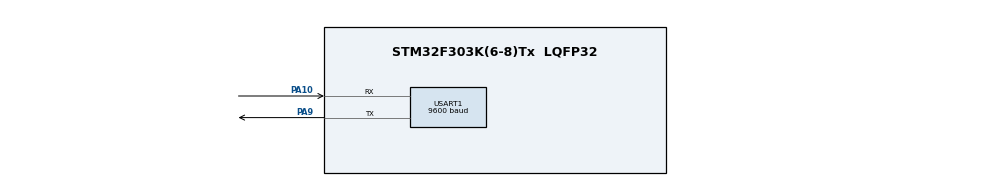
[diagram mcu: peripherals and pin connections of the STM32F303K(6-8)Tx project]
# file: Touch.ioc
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Mcu.Family=STM32F3
Mcu.Name=STM32F303K(6-8)Tx
Mcu.Package=LQFP32
NVIC.PriorityGroup=NVIC_PRIORITYGROUP_4
PA10.Mode=Asynchronous
PA10.Signal=USART1_RX
PA13.GPIO_Label=SWDIO
PA13.Mode=Serial_Wire
PA13.Signal=SYS_JTMS-SWDIO
PA14.GPIO_Label=SWCLK
PA14.Mode=Serial_Wire
PA14.Signal=SYS_JTCK-SWCLK
PA15.GPIO_Label=VCP_RX
PA15.Signal=USART2_RX
PA2.GPIO_Label=VCP_TX
PA2.Signal=USART2_TX
PA9.Mode=Asynchronous
PA9.Signal=USART1_TX
PF0\ /\ OSC_IN.GPIO_Label=MCO
PF0\ /\ OSC_IN.Signal=RCC_OSC_IN
ProjectManager.HeapSize=0x200
ProjectManager.StackSize=0x400
ProjectManager.TargetToolchain=SW4STM32
RCC.AHBFreq_Value=8000000
RCC.APB1Freq_Value=8000000
RCC.APB2Freq_Value=8000000
RCC.CortexFreq_Value=8000000
RCC.HSE_VALUE=8000000
RCC.HSI_VALUE=8000000
RCC.SYSCLKFreq_VALUE=8000000
USART1.BaudRate=9600
USART1.VirtualMode-Asynchronous=VM_ASYNC
USART1.WordLength=WORDLENGTH_8B
board=NUCLEO-F303K8

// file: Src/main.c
/**
  ******************************************************************************
  * @file           : main.c
  * @brief          : Main program body
  ******************************************************************************
  ** This notice applies to any and all portions of this file
  * that are not between comment pairs USER CODE BEGIN and
  * USER CODE END. Other portions of this file, whether
  * inserted by the user or by software development tools
  * are owned by their respective copyright owners.
  *
  * COPYRIGHT(c) 2018 STMicroelectronics
  *
  * Redistribution and use in source and binary forms, with or without modification,
  * are permitted provided that the following conditions are met:
  *   1. Redistributions of source code must retain the above copyright notice,
  *      this list of conditions and the following disclaimer.
  *   2. Redistributions in binary form must reproduce the above copyright notice,
  *      this list of conditions and the following disclaimer in the documentation
  *      and/or other materials provided with the distribution.
  *   3. Neither the name of STMicroelectronics nor the names of its contributors
  *      may be used to endorse or promote products derived from this software
  *      without specific prior written permission.
  *
  * THIS SOFTWARE IS PROVIDED BY THE COPYRIGHT HOLDERS AND CONTRIBUTORS "AS IS"
  * AND ANY EXPRESS OR IMPLIED WARRANTIES, INCLUDING, BUT NOT LIMITED TO, THE
  * IMPLIED WARRANTIES OF MERCHANTABILITY AND FITNESS FOR A PARTICULAR PURPOSE ARE
  * DISCLAIMED. IN NO EVENT SHALL THE COPYRIGHT HOLDER OR CONTRIBUTORS BE LIABLE
  * FOR ANY DIRECT, INDIRECT, INCIDENTAL, SPECIAL, EXEMPLARY, OR CONSEQUENTIAL
  * DAMAGES (INCLUDING, BUT NOT LIMITED TO, PROCUREMENT OF SUBSTITUTE GOODS OR
  * SERVICES; LOSS OF USE, DATA, OR PROFITS; OR BUSINESS INTERRUPTION) HOWEVER
  * CAUSED AND ON ANY THEORY OF LIABILITY, WHETHER IN CONTRACT, STRICT LIABILITY,
  * OR TORT (INCLUDING NEGLIGENCE OR OTHERWISE) ARISING IN ANY WAY OUT OF THE USE
  * OF THIS SOFTWARE, EVEN IF ADVISED OF THE POSSIBILITY OF SUCH DAMAGE.
  *
  ******************************************************************************
  */
#include "main.h"
#include "stm32f0xx_hal.h"

/* USER CODE BEGIN Includes */
#include "touch.h"
#include "identification.h"
/* USER CODE END Includes */

UART_HandleTypeDef huart1;

/* USER CODE BEGIN PV */
/* Private variables ---------------------------------------------------------*/

/* USER CODE END PV */

void SystemClock_Config(void);
static void MX_GPIO_Init(void);
static void MX_USART1_UART_Init(void);

/* USER CODE BEGIN PFP */
/* Private function prototypes -----------------------------------------------*/

/* USER CODE END PFP */

int main(void)
{
  /* USER CODE BEGIN 1 */
	//int light = 0;
  /* USER CODE END 1 */

  /* MCU Configuration----------------------------------------------------------*/

  /* Reset of all peripherals, Initializes the Flash interface and the Systick. */
  HAL_Init();

  /* Configure the system clock */
  SystemClock_Config();

  /* Initialize all configured peripherals */
  MX_GPIO_Init();
  MX_USART1_UART_Init();
  /* USER CODE BEGIN 2 */
  touch_open(0);
  touch_bakcklight(1);
  printf("Touch Connected");
  /* USER CODE END 2 */

  /* Infinite loop */
  while (1)
  {

  /* USER CODE BEGIN 3 */
//	  touch_bakcklight(0);
//	  HAL_Delay(1000);
//

//	  HAL_Delay(1000);
//	  touch_enroll_start(10);
//	  while(!touch_is_press_finger()){
//		  HAL_Delay(100);
//	  }
//		touch_capture_finger();
//		touch_enroll_1();
//		  while(touch_is_press_finger()){
//			  HAL_Delay(100);
//		  }
//		  while(!touch_is_press_finger()){
//			  HAL_Delay(100);
//		  }
//		touch_capture_finger();
//		touch_enroll_2();
//		  while(touch_is_press_finger()){
//			  HAL_Delay(100);
//		  }
//		  while(!touch_is_press_finger()){
//			  HAL_Delay(100);
//		  }
//		touch_capture_finger();
//		touch_enroll_3(0);
//		  while(touch_is_press_finger()){
//			  HAL_Delay(100);
//		  }
		//	  touch_enrolled_count();
//	  identification_check();
	  identification_enroll_user();
	  HAL_Delay(3000);
  }
  /* USER CODE END 3 */

}

void SystemClock_Config(void)
{

  RCC_OscInitTypeDef RCC_OscInitStruct;
  RCC_ClkInitTypeDef RCC_ClkInitStruct;
  RCC_PeriphCLKInitTypeDef PeriphClkInit;

    /**Initializes the CPU, AHB and APB busses clocks
    */
  RCC_OscInitStruct.OscillatorType = RCC_OSCILLATORTYPE_HSI;
  RCC_OscInitStruct.HSIState = RCC_HSI_ON;
  RCC_OscInitStruct.HSICalibrationValue = 16;
  RCC_OscInitStruct.PLL.PLLState = RCC_PLL_ON;
  RCC_OscInitStruct.PLL.PLLSource = RCC_PLLSOURCE_HSI;
  RCC_OscInitStruct.PLL.PLLMUL = RCC_PLL_MUL12;
  RCC_OscInitStruct.PLL.PREDIV = RCC_PREDIV_DIV1;
  if (HAL_RCC_OscConfig(&RCC_OscInitStruct) != HAL_OK)
  {
    _Error_Handler(__FILE__, __LINE__);
  }

    /**Initializes the CPU, AHB and APB busses clocks
    */
  RCC_ClkInitStruct.ClockType = RCC_CLOCKTYPE_HCLK|RCC_CLOCKTYPE_SYSCLK
                              |RCC_CLOCKTYPE_PCLK1;
  RCC_ClkInitStruct.SYSCLKSource = RCC_SYSCLKSOURCE_PLLCLK;
  RCC_ClkInitStruct.AHBCLKDivider = RCC_SYSCLK_DIV1;
  RCC_ClkInitStruct.APB1CLKDivider = RCC_HCLK_DIV1;

  if (HAL_RCC_ClockConfig(&RCC_ClkInitStruct, FLASH_LATENCY_1) != HAL_OK)
  {
    _Error_Handler(__FILE__, __LINE__);
  }

  PeriphClkInit.PeriphClockSelection = RCC_PERIPHCLK_USART1;
  PeriphClkInit.Usart1ClockSelection = RCC_USART1CLKSOURCE_PCLK1;
  if (HAL_RCCEx_PeriphCLKConfig(&PeriphClkInit) != HAL_OK)
  {
    _Error_Handler(__FILE__, __LINE__);
  }

    /**Configure the Systick interrupt time
    */
  HAL_SYSTICK_Config(HAL_RCC_GetHCLKFreq()/1000);

    /**Configure the Systick
    */
  HAL_SYSTICK_CLKSourceConfig(SYSTICK_CLKSOURCE_HCLK);

  /* SysTick_IRQn interrupt configuration */
  HAL_NVIC_SetPriority(SysTick_IRQn, 0, 0);
}

/* USART1 init function */
static void MX_USART1_UART_Init(void)
{

  huart1.Instance = USART1;
  huart1.Init.BaudRate = 9600;
  huart1.Init.WordLength = UART_WORDLENGTH_8B;
  huart1.Init.StopBits = UART_STOPBITS_1;
  huart1.Init.Parity = UART_PARITY_NONE;
  huart1.Init.Mode = UART_MODE_TX_RX;
  huart1.Init.HwFlowCtl = UART_HWCONTROL_NONE;
  huart1.Init.OverSampling = UART_OVERSAMPLING_16;
  huart1.Init.OneBitSampling = UART_ONE_BIT_SAMPLE_DISABLE;
  huart1.AdvancedInit.AdvFeatureInit = UART_ADVFEATURE_NO_INIT;
  if (HAL_UART_Init(&huart1) != HAL_OK)
  {
    _Error_Handler(__FILE__, __LINE__);
  }

}

/** Configure pins as
        * Analog
        * Input
        * Output
        * EVENT_OUT
        * EXTI
*/
static void MX_GPIO_Init(void)
{

  GPIO_InitTypeDef GPIO_InitStruct;

  /* GPIO Ports Clock Enable */
  __HAL_RCC_GPIOA_CLK_ENABLE();
  __HAL_RCC_GPIOC_CLK_ENABLE();

  /*Configure GPIO pin Output Level */
  HAL_GPIO_WritePin(GPIOC, LD4_Pin|LD3_Pin, GPIO_PIN_RESET);

  /*Configure GPIO pin : B1_Pin */
  GPIO_InitStruct.Pin = B1_Pin;
  GPIO_InitStruct.Mode = GPIO_MODE_EVT_RISING;
  GPIO_InitStruct.Pull = GPIO_NOPULL;
  HAL_GPIO_Init(B1_GPIO_Port, &GPIO_InitStruct);

  /*Configure GPIO pins : LD4_Pin LD3_Pin */
  GPIO_InitStruct.Pin = LD4_Pin|LD3_Pin;
  GPIO_InitStruct.Mode = GPIO_MODE_OUTPUT_PP;
  GPIO_InitStruct.Pull = GPIO_NOPULL;
  GPIO_InitStruct.Speed = GPIO_SPEED_FREQ_LOW;
  HAL_GPIO_Init(GPIOC, &GPIO_InitStruct);

}

void _Error_Handler(char *file, int line)
{
  while(1)
  {
  }
}

/************************ (C) COPYRIGHT STMicroelectronics *****END OF FILE****/
